# npu_sram_bank abstract LEF. GENERATED by layout/flow/gen-macro-lef.py; do not edit.
# Abstract view only (MACRO/PIN/OBS): no internal layout, no bitcell. Footprint rule: decision 0005.
VERSION 5.8 ;
BUSBITCHARS "[]" ;
DIVIDERCHAR "/" ;

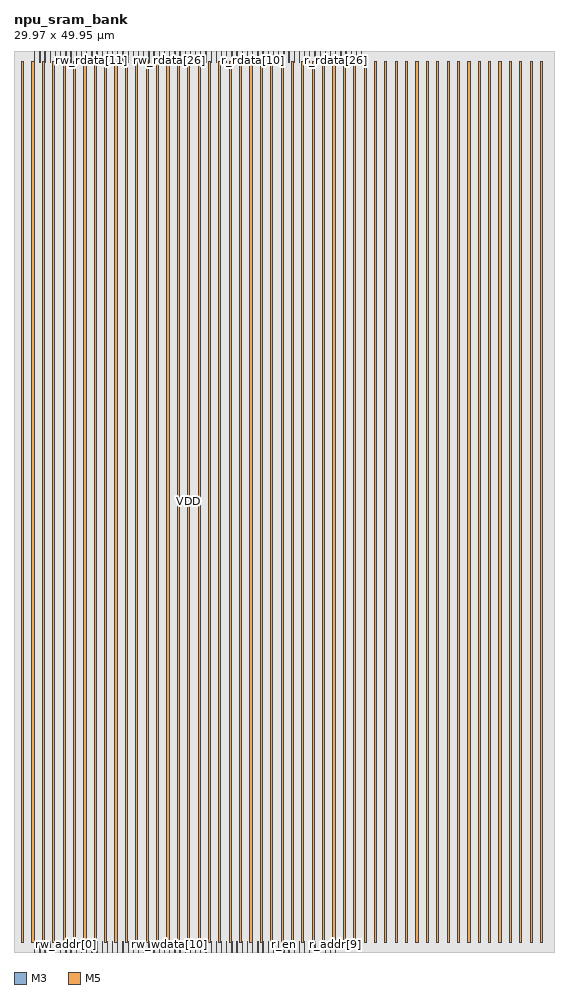
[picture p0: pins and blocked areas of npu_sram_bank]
MACRO npu_sram_bank
  CLASS BLOCK ;
  ORIGIN 0 0 ;
  FOREIGN npu_sram_bank 0 0 ;
  SIZE 29.970 BY 49.950 ;
  SYMMETRY X Y ;
  PIN clk
    DIRECTION INPUT ;
    USE SIGNAL ;
    PORT
      LAYER M3 ;
        RECT 1.143 0.000 1.161 0.576 ;
    END
  END clk
  PIN rw_en
    DIRECTION INPUT ;
    USE SIGNAL ;
    PORT
      LAYER M3 ;
        RECT 1.431 0.000 1.449 0.576 ;
    END
  END rw_en
  PIN rw_we[0]
    DIRECTION INPUT ;
    USE SIGNAL ;
    PORT
      LAYER M3 ;
        RECT 1.719 0.000 1.737 0.576 ;
    END
  END rw_we[0]
  PIN rw_we[1]
    DIRECTION INPUT ;
    USE SIGNAL ;
    PORT
      LAYER M3 ;
        RECT 2.007 0.000 2.025 0.576 ;
    END
  END rw_we[1]
  PIN rw_we[2]
    DIRECTION INPUT ;
    USE SIGNAL ;
    PORT
      LAYER M3 ;
        RECT 2.295 0.000 2.313 0.576 ;
    END
  END rw_we[2]
  PIN rw_we[3]
    DIRECTION INPUT ;
    USE SIGNAL ;
    PORT
      LAYER M3 ;
        RECT 2.583 0.000 2.601 0.576 ;
    END
  END rw_we[3]
  PIN rw_addr[0]
    DIRECTION INPUT ;
    USE SIGNAL ;
    PORT
      LAYER M3 ;
        RECT 2.871 0.000 2.889 0.576 ;
    END
  END rw_addr[0]
  PIN rw_addr[1]
    DIRECTION INPUT ;
    USE SIGNAL ;
    PORT
      LAYER M3 ;
        RECT 3.159 0.000 3.177 0.576 ;
    END
  END rw_addr[1]
  PIN rw_addr[2]
    DIRECTION INPUT ;
    USE SIGNAL ;
    PORT
      LAYER M3 ;
        RECT 3.447 0.000 3.465 0.576 ;
    END
  END rw_addr[2]
  PIN rw_addr[3]
    DIRECTION INPUT ;
    USE SIGNAL ;
    PORT
      LAYER M3 ;
        RECT 3.735 0.000 3.753 0.576 ;
    END
  END rw_addr[3]
  PIN rw_addr[4]
    DIRECTION INPUT ;
    USE SIGNAL ;
    PORT
      LAYER M3 ;
        RECT 4.023 0.000 4.041 0.576 ;
    END
  END rw_addr[4]
  PIN rw_addr[5]
    DIRECTION INPUT ;
    USE SIGNAL ;
    PORT
      LAYER M3 ;
        RECT 4.311 0.000 4.329 0.576 ;
    END
  END rw_addr[5]
  PIN rw_addr[6]
    DIRECTION INPUT ;
    USE SIGNAL ;
    PORT
      LAYER M3 ;
        RECT 4.599 0.000 4.617 0.576 ;
    END
  END rw_addr[6]
  PIN rw_addr[7]
    DIRECTION INPUT ;
    USE SIGNAL ;
    PORT
      LAYER M3 ;
        RECT 4.887 0.000 4.905 0.576 ;
    END
  END rw_addr[7]
  PIN rw_addr[8]
    DIRECTION INPUT ;
    USE SIGNAL ;
    PORT
      LAYER M3 ;
        RECT 5.175 0.000 5.193 0.576 ;
    END
  END rw_addr[8]
  PIN rw_addr[9]
    DIRECTION INPUT ;
    USE SIGNAL ;
    PORT
      LAYER M3 ;
        RECT 5.463 0.000 5.481 0.576 ;
    END
  END rw_addr[9]
  PIN rw_wdata[0]
    DIRECTION INPUT ;
    USE SIGNAL ;
    PORT
      LAYER M3 ;
        RECT 5.751 0.000 5.769 0.576 ;
    END
  END rw_wdata[0]
  PIN rw_wdata[1]
    DIRECTION INPUT ;
    USE SIGNAL ;
    PORT
      LAYER M3 ;
        RECT 6.039 0.000 6.057 0.576 ;
    END
  END rw_wdata[1]
  PIN rw_wdata[2]
    DIRECTION INPUT ;
    USE SIGNAL ;
    PORT
      LAYER M3 ;
        RECT 6.327 0.000 6.345 0.576 ;
    END
  END rw_wdata[2]
  PIN rw_wdata[3]
    DIRECTION INPUT ;
    USE SIGNAL ;
    PORT
      LAYER M3 ;
        RECT 6.615 0.000 6.633 0.576 ;
    END
  END rw_wdata[3]
  PIN rw_wdata[4]
    DIRECTION INPUT ;
    USE SIGNAL ;
    PORT
      LAYER M3 ;
        RECT 6.903 0.000 6.921 0.576 ;
    END
  END rw_wdata[4]
  PIN rw_wdata[5]
    DIRECTION INPUT ;
    USE SIGNAL ;
    PORT
      LAYER M3 ;
        RECT 7.191 0.000 7.209 0.576 ;
    END
  END rw_wdata[5]
  PIN rw_wdata[6]
    DIRECTION INPUT ;
    USE SIGNAL ;
    PORT
      LAYER M3 ;
        RECT 7.479 0.000 7.497 0.576 ;
    END
  END rw_wdata[6]
  PIN rw_wdata[7]
    DIRECTION INPUT ;
    USE SIGNAL ;
    PORT
      LAYER M3 ;
        RECT 7.767 0.000 7.785 0.576 ;
    END
  END rw_wdata[7]
  PIN rw_wdata[8]
    DIRECTION INPUT ;
    USE SIGNAL ;
    PORT
      LAYER M3 ;
        RECT 8.055 0.000 8.073 0.576 ;
    END
  END rw_wdata[8]
  PIN rw_wdata[9]
    DIRECTION INPUT ;
    USE SIGNAL ;
    PORT
      LAYER M3 ;
        RECT 8.343 0.000 8.361 0.576 ;
    END
  END rw_wdata[9]
  PIN rw_wdata[10]
    DIRECTION INPUT ;
    USE SIGNAL ;
    PORT
      LAYER M3 ;
        RECT 8.631 0.000 8.649 0.576 ;
    END
  END rw_wdata[10]
  PIN rw_wdata[11]
    DIRECTION INPUT ;
    USE SIGNAL ;
    PORT
      LAYER M3 ;
        RECT 8.919 0.000 8.937 0.576 ;
    END
  END rw_wdata[11]
  PIN rw_wdata[12]
    DIRECTION INPUT ;
    USE SIGNAL ;
    PORT
      LAYER M3 ;
        RECT 9.207 0.000 9.225 0.576 ;
    END
  END rw_wdata[12]
  PIN rw_wdata[13]
    DIRECTION INPUT ;
    USE SIGNAL ;
    PORT
      LAYER M3 ;
        RECT 9.495 0.000 9.513 0.576 ;
    END
  END rw_wdata[13]
  PIN rw_wdata[14]
    DIRECTION INPUT ;
    USE SIGNAL ;
    PORT
      LAYER M3 ;
        RECT 9.783 0.000 9.801 0.576 ;
    END
  END rw_wdata[14]
  PIN rw_wdata[15]
    DIRECTION INPUT ;
    USE SIGNAL ;
    PORT
      LAYER M3 ;
        RECT 10.071 0.000 10.089 0.576 ;
    END
  END rw_wdata[15]
  PIN rw_wdata[16]
    DIRECTION INPUT ;
    USE SIGNAL ;
    PORT
      LAYER M3 ;
        RECT 10.359 0.000 10.377 0.576 ;
    END
  END rw_wdata[16]
  PIN rw_wdata[17]
    DIRECTION INPUT ;
    USE SIGNAL ;
    PORT
      LAYER M3 ;
        RECT 10.647 0.000 10.665 0.576 ;
    END
  END rw_wdata[17]
  PIN rw_wdata[18]
    DIRECTION INPUT ;
    USE SIGNAL ;
    PORT
      LAYER M3 ;
        RECT 10.935 0.000 10.953 0.576 ;
    END
  END rw_wdata[18]
  PIN rw_wdata[19]
    DIRECTION INPUT ;
    USE SIGNAL ;
    PORT
      LAYER M3 ;
        RECT 11.223 0.000 11.241 0.576 ;
    END
  END rw_wdata[19]
  PIN rw_wdata[20]
    DIRECTION INPUT ;
    USE SIGNAL ;
    PORT
      LAYER M3 ;
        RECT 11.511 0.000 11.529 0.576 ;
    END
  END rw_wdata[20]
  PIN rw_wdata[21]
    DIRECTION INPUT ;
    USE SIGNAL ;
    PORT
      LAYER M3 ;
        RECT 11.799 0.000 11.817 0.576 ;
    END
  END rw_wdata[21]
  PIN rw_wdata[22]
    DIRECTION INPUT ;
    USE SIGNAL ;
    PORT
      LAYER M3 ;
        RECT 12.087 0.000 12.105 0.576 ;
    END
  END rw_wdata[22]
  PIN rw_wdata[23]
    DIRECTION INPUT ;
    USE SIGNAL ;
    PORT
      LAYER M3 ;
        RECT 12.375 0.000 12.393 0.576 ;
    END
  END rw_wdata[23]
  PIN rw_wdata[24]
    DIRECTION INPUT ;
    USE SIGNAL ;
    PORT
      LAYER M3 ;
        RECT 12.663 0.000 12.681 0.576 ;
    END
  END rw_wdata[24]
  PIN rw_wdata[25]
    DIRECTION INPUT ;
    USE SIGNAL ;
    PORT
      LAYER M3 ;
        RECT 12.951 0.000 12.969 0.576 ;
    END
  END rw_wdata[25]
  PIN rw_wdata[26]
    DIRECTION INPUT ;
    USE SIGNAL ;
    PORT
      LAYER M3 ;
        RECT 13.239 0.000 13.257 0.576 ;
    END
  END rw_wdata[26]
  PIN rw_wdata[27]
    DIRECTION INPUT ;
    USE SIGNAL ;
    PORT
      LAYER M3 ;
        RECT 13.527 0.000 13.545 0.576 ;
    END
  END rw_wdata[27]
  PIN rw_wdata[28]
    DIRECTION INPUT ;
    USE SIGNAL ;
    PORT
      LAYER M3 ;
        RECT 13.815 0.000 13.833 0.576 ;
    END
  END rw_wdata[28]
  PIN rw_wdata[29]
    DIRECTION INPUT ;
    USE SIGNAL ;
    PORT
      LAYER M3 ;
        RECT 14.103 0.000 14.121 0.576 ;
    END
  END rw_wdata[29]
  PIN rw_wdata[30]
    DIRECTION INPUT ;
    USE SIGNAL ;
    PORT
      LAYER M3 ;
        RECT 14.391 0.000 14.409 0.576 ;
    END
  END rw_wdata[30]
  PIN rw_wdata[31]
    DIRECTION INPUT ;
    USE SIGNAL ;
    PORT
      LAYER M3 ;
        RECT 14.679 0.000 14.697 0.576 ;
    END
  END rw_wdata[31]
  PIN r_en
    DIRECTION INPUT ;
    USE SIGNAL ;
    PORT
      LAYER M3 ;
        RECT 14.967 0.000 14.985 0.576 ;
    END
  END r_en
  PIN r_addr[0]
    DIRECTION INPUT ;
    USE SIGNAL ;
    PORT
      LAYER M3 ;
        RECT 15.255 0.000 15.273 0.576 ;
    END
  END r_addr[0]
  PIN r_addr[1]
    DIRECTION INPUT ;
    USE SIGNAL ;
    PORT
      LAYER M3 ;
        RECT 15.543 0.000 15.561 0.576 ;
    END
  END r_addr[1]
  PIN r_addr[2]
    DIRECTION INPUT ;
    USE SIGNAL ;
    PORT
      LAYER M3 ;
        RECT 15.831 0.000 15.849 0.576 ;
    END
  END r_addr[2]
  PIN r_addr[3]
    DIRECTION INPUT ;
    USE SIGNAL ;
    PORT
      LAYER M3 ;
        RECT 16.119 0.000 16.137 0.576 ;
    END
  END r_addr[3]
  PIN r_addr[4]
    DIRECTION INPUT ;
    USE SIGNAL ;
    PORT
      LAYER M3 ;
        RECT 16.407 0.000 16.425 0.576 ;
    END
  END r_addr[4]
  PIN r_addr[5]
    DIRECTION INPUT ;
    USE SIGNAL ;
    PORT
      LAYER M3 ;
        RECT 16.695 0.000 16.713 0.576 ;
    END
  END r_addr[5]
  PIN r_addr[6]
    DIRECTION INPUT ;
    USE SIGNAL ;
    PORT
      LAYER M3 ;
        RECT 16.983 0.000 17.001 0.576 ;
    END
  END r_addr[6]
  PIN r_addr[7]
    DIRECTION INPUT ;
    USE SIGNAL ;
    PORT
      LAYER M3 ;
        RECT 17.271 0.000 17.289 0.576 ;
    END
  END r_addr[7]
  PIN r_addr[8]
    DIRECTION INPUT ;
    USE SIGNAL ;
    PORT
      LAYER M3 ;
        RECT 17.559 0.000 17.577 0.576 ;
    END
  END r_addr[8]
  PIN r_addr[9]
    DIRECTION INPUT ;
    USE SIGNAL ;
    PORT
      LAYER M3 ;
        RECT 17.847 0.000 17.865 0.576 ;
    END
  END r_addr[9]
  PIN rw_rdata[0]
    DIRECTION OUTPUT ;
    USE SIGNAL ;
    PORT
      LAYER M3 ;
        RECT 1.143 49.374 1.161 49.950 ;
    END
  END rw_rdata[0]
  PIN rw_rdata[1]
    DIRECTION OUTPUT ;
    USE SIGNAL ;
    PORT
      LAYER M3 ;
        RECT 1.431 49.374 1.449 49.950 ;
    END
  END rw_rdata[1]
  PIN rw_rdata[2]
    DIRECTION OUTPUT ;
    USE SIGNAL ;
    PORT
      LAYER M3 ;
        RECT 1.719 49.374 1.737 49.950 ;
    END
  END rw_rdata[2]
  PIN rw_rdata[3]
    DIRECTION OUTPUT ;
    USE SIGNAL ;
    PORT
      LAYER M3 ;
        RECT 2.007 49.374 2.025 49.950 ;
    END
  END rw_rdata[3]
  PIN rw_rdata[4]
    DIRECTION OUTPUT ;
    USE SIGNAL ;
    PORT
      LAYER M3 ;
        RECT 2.295 49.374 2.313 49.950 ;
    END
  END rw_rdata[4]
  PIN rw_rdata[5]
    DIRECTION OUTPUT ;
    USE SIGNAL ;
    PORT
      LAYER M3 ;
        RECT 2.583 49.374 2.601 49.950 ;
    END
  END rw_rdata[5]
  PIN rw_rdata[6]
    DIRECTION OUTPUT ;
    USE SIGNAL ;
    PORT
      LAYER M3 ;
        RECT 2.871 49.374 2.889 49.950 ;
    END
  END rw_rdata[6]
  PIN rw_rdata[7]
    DIRECTION OUTPUT ;
    USE SIGNAL ;
    PORT
      LAYER M3 ;
        RECT 3.159 49.374 3.177 49.950 ;
    END
  END rw_rdata[7]
  PIN rw_rdata[8]
    DIRECTION OUTPUT ;
    USE SIGNAL ;
    PORT
      LAYER M3 ;
        RECT 3.447 49.374 3.465 49.950 ;
    END
  END rw_rdata[8]
  PIN rw_rdata[9]
    DIRECTION OUTPUT ;
    USE SIGNAL ;
    PORT
      LAYER M3 ;
        RECT 3.735 49.374 3.753 49.950 ;
    END
  END rw_rdata[9]
  PIN rw_rdata[10]
    DIRECTION OUTPUT ;
    USE SIGNAL ;
    PORT
      LAYER M3 ;
        RECT 4.023 49.374 4.041 49.950 ;
    END
  END rw_rdata[10]
  PIN rw_rdata[11]
    DIRECTION OUTPUT ;
    USE SIGNAL ;
    PORT
      LAYER M3 ;
        RECT 4.311 49.374 4.329 49.950 ;
    END
  END rw_rdata[11]
  PIN rw_rdata[12]
    DIRECTION OUTPUT ;
    USE SIGNAL ;
    PORT
      LAYER M3 ;
        RECT 4.599 49.374 4.617 49.950 ;
    END
  END rw_rdata[12]
  PIN rw_rdata[13]
    DIRECTION OUTPUT ;
    USE SIGNAL ;
    PORT
      LAYER M3 ;
        RECT 4.887 49.374 4.905 49.950 ;
    END
  END rw_rdata[13]
  PIN rw_rdata[14]
    DIRECTION OUTPUT ;
    USE SIGNAL ;
    PORT
      LAYER M3 ;
        RECT 5.175 49.374 5.193 49.950 ;
    END
  END rw_rdata[14]
  PIN rw_rdata[15]
    DIRECTION OUTPUT ;
    USE SIGNAL ;
    PORT
      LAYER M3 ;
        RECT 5.463 49.374 5.481 49.950 ;
    END
  END rw_rdata[15]
  PIN rw_rdata[16]
    DIRECTION OUTPUT ;
    USE SIGNAL ;
    PORT
      LAYER M3 ;
        RECT 5.751 49.374 5.769 49.950 ;
    END
  END rw_rdata[16]
  PIN rw_rdata[17]
    DIRECTION OUTPUT ;
    USE SIGNAL ;
    PORT
      LAYER M3 ;
        RECT 6.039 49.374 6.057 49.950 ;
    END
  END rw_rdata[17]
  PIN rw_rdata[18]
    DIRECTION OUTPUT ;
    USE SIGNAL ;
    PORT
      LAYER M3 ;
        RECT 6.327 49.374 6.345 49.950 ;
    END
  END rw_rdata[18]
  PIN rw_rdata[19]
    DIRECTION OUTPUT ;
    USE SIGNAL ;
    PORT
      LAYER M3 ;
        RECT 6.615 49.374 6.633 49.950 ;
    END
  END rw_rdata[19]
  PIN rw_rdata[20]
    DIRECTION OUTPUT ;
    USE SIGNAL ;
    PORT
      LAYER M3 ;
        RECT 6.903 49.374 6.921 49.950 ;
    END
  END rw_rdata[20]
  PIN rw_rdata[21]
    DIRECTION OUTPUT ;
    USE SIGNAL ;
    PORT
      LAYER M3 ;
        RECT 7.191 49.374 7.209 49.950 ;
    END
  END rw_rdata[21]
  PIN rw_rdata[22]
    DIRECTION OUTPUT ;
    USE SIGNAL ;
    PORT
      LAYER M3 ;
        RECT 7.479 49.374 7.497 49.950 ;
    END
  END rw_rdata[22]
  PIN rw_rdata[23]
    DIRECTION OUTPUT ;
    USE SIGNAL ;
    PORT
      LAYER M3 ;
        RECT 7.767 49.374 7.785 49.950 ;
    END
  END rw_rdata[23]
  PIN rw_rdata[24]
    DIRECTION OUTPUT ;
    USE SIGNAL ;
    PORT
      LAYER M3 ;
        RECT 8.055 49.374 8.073 49.950 ;
    END
  END rw_rdata[24]
  PIN rw_rdata[25]
    DIRECTION OUTPUT ;
    USE SIGNAL ;
    PORT
      LAYER M3 ;
        RECT 8.343 49.374 8.361 49.950 ;
    END
  END rw_rdata[25]
  PIN rw_rdata[26]
    DIRECTION OUTPUT ;
    USE SIGNAL ;
    PORT
      LAYER M3 ;
        RECT 8.631 49.374 8.649 49.950 ;
    END
  END rw_rdata[26]
  PIN rw_rdata[27]
    DIRECTION OUTPUT ;
    USE SIGNAL ;
    PORT
      LAYER M3 ;
        RECT 8.919 49.374 8.937 49.950 ;
    END
  END rw_rdata[27]
  PIN rw_rdata[28]
    DIRECTION OUTPUT ;
    USE SIGNAL ;
    PORT
      LAYER M3 ;
        RECT 9.207 49.374 9.225 49.950 ;
    END
  END rw_rdata[28]
  PIN rw_rdata[29]
    DIRECTION OUTPUT ;
    USE SIGNAL ;
    PORT
      LAYER M3 ;
        RECT 9.495 49.374 9.513 49.950 ;
    END
  END rw_rdata[29]
  PIN rw_rdata[30]
    DIRECTION OUTPUT ;
    USE SIGNAL ;
    PORT
      LAYER M3 ;
        RECT 9.783 49.374 9.801 49.950 ;
    END
  END rw_rdata[30]
  PIN rw_rdata[31]
    DIRECTION OUTPUT ;
    USE SIGNAL ;
    PORT
      LAYER M3 ;
        RECT 10.071 49.374 10.089 49.950 ;
    END
  END rw_rdata[31]
  PIN r_rdata[0]
    DIRECTION OUTPUT ;
    USE SIGNAL ;
    PORT
      LAYER M3 ;
        RECT 10.359 49.374 10.377 49.950 ;
    END
  END r_rdata[0]
  PIN r_rdata[1]
    DIRECTION OUTPUT ;
    USE SIGNAL ;
    PORT
      LAYER M3 ;
        RECT 10.647 49.374 10.665 49.950 ;
    END
  END r_rdata[1]
  PIN r_rdata[2]
    DIRECTION OUTPUT ;
    USE SIGNAL ;
    PORT
      LAYER M3 ;
        RECT 10.935 49.374 10.953 49.950 ;
    END
  END r_rdata[2]
  PIN r_rdata[3]
    DIRECTION OUTPUT ;
    USE SIGNAL ;
    PORT
      LAYER M3 ;
        RECT 11.223 49.374 11.241 49.950 ;
    END
  END r_rdata[3]
  PIN r_rdata[4]
    DIRECTION OUTPUT ;
    USE SIGNAL ;
    PORT
      LAYER M3 ;
        RECT 11.511 49.374 11.529 49.950 ;
    END
  END r_rdata[4]
  PIN r_rdata[5]
    DIRECTION OUTPUT ;
    USE SIGNAL ;
    PORT
      LAYER M3 ;
        RECT 11.799 49.374 11.817 49.950 ;
    END
  END r_rdata[5]
  PIN r_rdata[6]
    DIRECTION OUTPUT ;
    USE SIGNAL ;
    PORT
      LAYER M3 ;
        RECT 12.087 49.374 12.105 49.950 ;
    END
  END r_rdata[6]
  PIN r_rdata[7]
    DIRECTION OUTPUT ;
    USE SIGNAL ;
    PORT
      LAYER M3 ;
        RECT 12.375 49.374 12.393 49.950 ;
    END
  END r_rdata[7]
  PIN r_rdata[8]
    DIRECTION OUTPUT ;
    USE SIGNAL ;
    PORT
      LAYER M3 ;
        RECT 12.663 49.374 12.681 49.950 ;
    END
  END r_rdata[8]
  PIN r_rdata[9]
    DIRECTION OUTPUT ;
    USE SIGNAL ;
    PORT
      LAYER M3 ;
        RECT 12.951 49.374 12.969 49.950 ;
    END
  END r_rdata[9]
  PIN r_rdata[10]
    DIRECTION OUTPUT ;
    USE SIGNAL ;
    PORT
      LAYER M3 ;
        RECT 13.239 49.374 13.257 49.950 ;
    END
  END r_rdata[10]
  PIN r_rdata[11]
    DIRECTION OUTPUT ;
    USE SIGNAL ;
    PORT
      LAYER M3 ;
        RECT 13.527 49.374 13.545 49.950 ;
    END
  END r_rdata[11]
  PIN r_rdata[12]
    DIRECTION OUTPUT ;
    USE SIGNAL ;
    PORT
      LAYER M3 ;
        RECT 13.815 49.374 13.833 49.950 ;
    END
  END r_rdata[12]
  PIN r_rdata[13]
    DIRECTION OUTPUT ;
    USE SIGNAL ;
    PORT
      LAYER M3 ;
        RECT 14.103 49.374 14.121 49.950 ;
    END
  END r_rdata[13]
  PIN r_rdata[14]
    DIRECTION OUTPUT ;
    USE SIGNAL ;
    PORT
      LAYER M3 ;
        RECT 14.391 49.374 14.409 49.950 ;
    END
  END r_rdata[14]
  PIN r_rdata[15]
    DIRECTION OUTPUT ;
    USE SIGNAL ;
    PORT
      LAYER M3 ;
        RECT 14.679 49.374 14.697 49.950 ;
    END
  END r_rdata[15]
  PIN r_rdata[16]
    DIRECTION OUTPUT ;
    USE SIGNAL ;
    PORT
      LAYER M3 ;
        RECT 14.967 49.374 14.985 49.950 ;
    END
  END r_rdata[16]
  PIN r_rdata[17]
    DIRECTION OUTPUT ;
    USE SIGNAL ;
    PORT
      LAYER M3 ;
        RECT 15.255 49.374 15.273 49.950 ;
    END
  END r_rdata[17]
  PIN r_rdata[18]
    DIRECTION OUTPUT ;
    USE SIGNAL ;
    PORT
      LAYER M3 ;
        RECT 15.543 49.374 15.561 49.950 ;
    END
  END r_rdata[18]
  PIN r_rdata[19]
    DIRECTION OUTPUT ;
    USE SIGNAL ;
    PORT
      LAYER M3 ;
        RECT 15.831 49.374 15.849 49.950 ;
    END
  END r_rdata[19]
  PIN r_rdata[20]
    DIRECTION OUTPUT ;
    USE SIGNAL ;
    PORT
      LAYER M3 ;
        RECT 16.119 49.374 16.137 49.950 ;
    END
  END r_rdata[20]
  PIN r_rdata[21]
    DIRECTION OUTPUT ;
    USE SIGNAL ;
    PORT
      LAYER M3 ;
        RECT 16.407 49.374 16.425 49.950 ;
    END
  END r_rdata[21]
  PIN r_rdata[22]
    DIRECTION OUTPUT ;
    USE SIGNAL ;
    PORT
      LAYER M3 ;
        RECT 16.695 49.374 16.713 49.950 ;
    END
  END r_rdata[22]
  PIN r_rdata[23]
    DIRECTION OUTPUT ;
    USE SIGNAL ;
    PORT
      LAYER M3 ;
        RECT 16.983 49.374 17.001 49.950 ;
    END
  END r_rdata[23]
  PIN r_rdata[24]
    DIRECTION OUTPUT ;
    USE SIGNAL ;
    PORT
      LAYER M3 ;
        RECT 17.271 49.374 17.289 49.950 ;
    END
  END r_rdata[24]
  PIN r_rdata[25]
    DIRECTION OUTPUT ;
    USE SIGNAL ;
    PORT
      LAYER M3 ;
        RECT 17.559 49.374 17.577 49.950 ;
    END
  END r_rdata[25]
  PIN r_rdata[26]
    DIRECTION OUTPUT ;
    USE SIGNAL ;
    PORT
      LAYER M3 ;
        RECT 17.847 49.374 17.865 49.950 ;
    END
  END r_rdata[26]
  PIN r_rdata[27]
    DIRECTION OUTPUT ;
    USE SIGNAL ;
    PORT
      LAYER M3 ;
        RECT 18.135 49.374 18.153 49.950 ;
    END
  END r_rdata[27]
  PIN r_rdata[28]
    DIRECTION OUTPUT ;
    USE SIGNAL ;
    PORT
      LAYER M3 ;
        RECT 18.423 49.374 18.441 49.950 ;
    END
  END r_rdata[28]
  PIN r_rdata[29]
    DIRECTION OUTPUT ;
    USE SIGNAL ;
    PORT
      LAYER M3 ;
        RECT 18.711 49.374 18.729 49.950 ;
    END
  END r_rdata[29]
  PIN r_rdata[30]
    DIRECTION OUTPUT ;
    USE SIGNAL ;
    PORT
      LAYER M3 ;
        RECT 18.999 49.374 19.017 49.950 ;
    END
  END r_rdata[30]
  PIN r_rdata[31]
    DIRECTION OUTPUT ;
    USE SIGNAL ;
    PORT
      LAYER M3 ;
        RECT 19.287 49.374 19.305 49.950 ;
    END
  END r_rdata[31]
  PIN VDD
    DIRECTION INOUT ;
    USE POWER ;
    PORT
      LAYER M5 ;
        RECT 0.420 0.500 0.540 49.450 ;
        RECT 1.572 0.500 1.692 49.450 ;
        RECT 2.724 0.500 2.844 49.450 ;
        RECT 3.876 0.500 3.996 49.450 ;
        RECT 5.028 0.500 5.148 49.450 ;
        RECT 6.180 0.500 6.300 49.450 ;
        RECT 7.332 0.500 7.452 49.450 ;
        RECT 8.484 0.500 8.604 49.450 ;
        RECT 9.636 0.500 9.756 49.450 ;
        RECT 10.788 0.500 10.908 49.450 ;
        RECT 11.940 0.500 12.060 49.450 ;
        RECT 13.092 0.500 13.212 49.450 ;
        RECT 14.244 0.500 14.364 49.450 ;
        RECT 15.396 0.500 15.516 49.450 ;
        RECT 16.548 0.500 16.668 49.450 ;
        RECT 17.700 0.500 17.820 49.450 ;
        RECT 18.852 0.500 18.972 49.450 ;
        RECT 20.004 0.500 20.124 49.450 ;
        RECT 21.156 0.500 21.276 49.450 ;
        RECT 22.308 0.500 22.428 49.450 ;
        RECT 23.460 0.500 23.580 49.450 ;
        RECT 24.612 0.500 24.732 49.450 ;
        RECT 25.764 0.500 25.884 49.450 ;
        RECT 26.916 0.500 27.036 49.450 ;
        RECT 28.068 0.500 28.188 49.450 ;
        RECT 29.220 0.500 29.340 49.450 ;
    END
  END VDD
  PIN VSS
    DIRECTION INOUT ;
    USE GROUND ;
    PORT
      LAYER M5 ;
        RECT 0.996 0.500 1.116 49.450 ;
        RECT 2.148 0.500 2.268 49.450 ;
        RECT 3.300 0.500 3.420 49.450 ;
        RECT 4.452 0.500 4.572 49.450 ;
        RECT 5.604 0.500 5.724 49.450 ;
        RECT 6.756 0.500 6.876 49.450 ;
        RECT 7.908 0.500 8.028 49.450 ;
        RECT 9.060 0.500 9.180 49.450 ;
        RECT 10.212 0.500 10.332 49.450 ;
        RECT 11.364 0.500 11.484 49.450 ;
        RECT 12.516 0.500 12.636 49.450 ;
        RECT 13.668 0.500 13.788 49.450 ;
        RECT 14.820 0.500 14.940 49.450 ;
        RECT 15.972 0.500 16.092 49.450 ;
        RECT 17.124 0.500 17.244 49.450 ;
        RECT 18.276 0.500 18.396 49.450 ;
        RECT 19.428 0.500 19.548 49.450 ;
        RECT 20.580 0.500 20.700 49.450 ;
        RECT 21.732 0.500 21.852 49.450 ;
        RECT 22.884 0.500 23.004 49.450 ;
        RECT 24.036 0.500 24.156 49.450 ;
        RECT 25.188 0.500 25.308 49.450 ;
        RECT 26.340 0.500 26.460 49.450 ;
        RECT 27.492 0.500 27.612 49.450 ;
        RECT 28.644 0.500 28.764 49.450 ;
    END
  END VSS
  OBS
    LAYER M1 ;
      RECT 0.000 0.000 29.970 49.950 ;
    LAYER M2 ;
      RECT 0.000 0.576 29.970 49.374 ;
    LAYER M3 ;
      RECT 0.000 0.576 29.970 49.374 ;
    LAYER M4 ;
      RECT 0.000 0.576 29.970 49.374 ;
    LAYER M5 ;
      RECT 0.000 0.000 29.970 49.950 ;
  END
END npu_sram_bank

END LIBRARY
